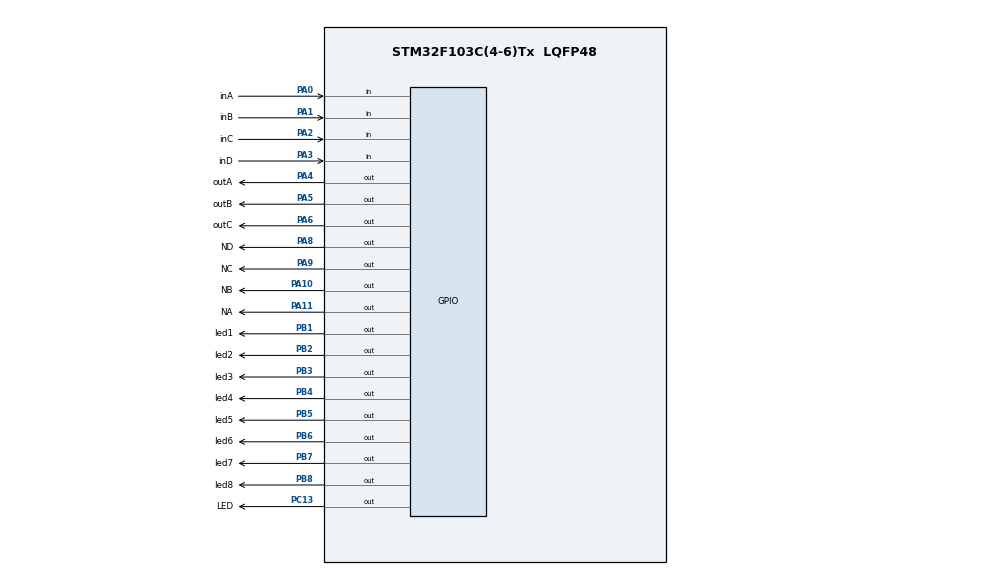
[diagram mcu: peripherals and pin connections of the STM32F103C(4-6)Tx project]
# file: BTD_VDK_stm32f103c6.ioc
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Mcu.Family=STM32F1
Mcu.Name=STM32F103C(4-6)Tx
Mcu.Package=LQFP48
NVIC.PriorityGroup=NVIC_PRIORITYGROUP_4
PA0-WKUP.GPIO_Label=inA
PA0-WKUP.GPIO_PuPd=GPIO_PULLUP
PA0-WKUP.Signal=GPIO_Input
PA1.GPIO_Label=inB
PA1.GPIO_PuPd=GPIO_PULLUP
PA1.Signal=GPIO_Input
PA10.GPIO_Label=NB
PA10.GPIO_Speed=GPIO_SPEED_FREQ_LOW
PA10.PinState=GPIO_PIN_RESET
PA10.Signal=GPIO_Output
PA11.GPIO_Label=NA
PA11.GPIO_Speed=GPIO_SPEED_FREQ_LOW
PA11.PinState=GPIO_PIN_RESET
PA11.Signal=GPIO_Output
PA13.Mode=Serial_Wire
PA13.Signal=SYS_JTMS-SWDIO
PA14.Mode=Serial_Wire
PA14.Signal=SYS_JTCK-SWCLK
PA2.GPIO_Label=inC
PA2.GPIO_PuPd=GPIO_PULLUP
PA2.Signal=GPIO_Input
PA3.GPIO_Label=inD
PA3.GPIO_PuPd=GPIO_PULLUP
PA3.Signal=GPIO_Input
PA4.GPIO_Label=outA
PA4.GPIO_Speed=GPIO_SPEED_FREQ_LOW
PA4.PinState=GPIO_PIN_RESET
PA4.Signal=GPIO_Output
PA5.GPIO_Label=outB
PA5.GPIO_Speed=GPIO_SPEED_FREQ_LOW
PA5.PinState=GPIO_PIN_RESET
PA5.Signal=GPIO_Output
PA6.GPIO_Label=outC
PA6.GPIO_Speed=GPIO_SPEED_FREQ_LOW
PA6.PinState=GPIO_PIN_RESET
PA6.Signal=GPIO_Output
PA8.GPIO_Label=ND
PA8.GPIO_Speed=GPIO_SPEED_FREQ_LOW
PA8.PinState=GPIO_PIN_RESET
PA8.Signal=GPIO_Output
PA9.GPIO_Label=NC
PA9.GPIO_Speed=GPIO_SPEED_FREQ_LOW
PA9.PinState=GPIO_PIN_RESET
PA9.Signal=GPIO_Output
PB1.GPIO_Label=led1
PB1.GPIO_Speed=GPIO_SPEED_FREQ_LOW
PB1.PinState=GPIO_PIN_RESET
PB1.Signal=GPIO_Output
PB2.GPIO_Label=led2
PB2.GPIO_Speed=GPIO_SPEED_FREQ_LOW
PB2.PinState=GPIO_PIN_RESET
PB2.Signal=GPIO_Output
PB3.GPIO_Label=led3
PB3.GPIO_Speed=GPIO_SPEED_FREQ_LOW
PB3.PinState=GPIO_PIN_RESET
PB3.Signal=GPIO_Output
PB4.GPIO_Label=led4
PB4.GPIO_Speed=GPIO_SPEED_FREQ_LOW
PB4.PinState=GPIO_PIN_RESET
PB4.Signal=GPIO_Output
PB5.GPIO_Label=led5
PB5.GPIO_Speed=GPIO_SPEED_FREQ_LOW
PB5.PinState=GPIO_PIN_RESET
PB5.Signal=GPIO_Output
PB6.GPIO_Label=led6
PB6.GPIO_Speed=GPIO_SPEED_FREQ_LOW
PB6.PinState=GPIO_PIN_RESET
PB6.Signal=GPIO_Output
PB7.GPIO_Label=led7
PB7.GPIO_Speed=GPIO_SPEED_FREQ_LOW
PB7.PinState=GPIO_PIN_RESET
PB7.Signal=GPIO_Output
PB8.GPIO_Label=led8
PB8.GPIO_Speed=GPIO_SPEED_FREQ_LOW
PB8.PinState=GPIO_PIN_RESET
PB8.Signal=GPIO_Output
PC13-TAMPER-RTC.GPIO_Label=LED
PC13-TAMPER-RTC.Signal=GPIO_Output
ProjectManager.HeapSize=0x200
ProjectManager.StackSize=0x400
ProjectManager.TargetToolchain=MDK-ARM V5.32
RCC.APB1Freq_Value=8000000
RCC.APB2Freq_Value=8000000
board=custom

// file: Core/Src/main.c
/* USER CODE BEGIN Header */
/**
  ******************************************************************************
  * @file           : main.c
  * @brief          : Main program body
  ******************************************************************************
  * @attention
  *
  * Copyright (c) 2022 STMicroelectronics.
  * All rights reserved.
  *
  * This software is licensed under terms that can be found in the LICENSE file
  * in the root directory of this software component.
  * If no LICENSE file comes with this software, it is provided AS-IS.
  *
  ******************************************************************************
  */
/* USER CODE END Header */
#include "main.h"

/* USER CODE BEGIN Includes */
#include "display.h"
#include "keypad.h"
#include "math.h"
/* USER CODE END Includes */

/* USER CODE BEGIN PM */
void PRESSKEY(unsigned char array[], uint8_t *t, uint8_t *enter);
/* USER CODE END PM */

/* USER CODE BEGIN PV */
uint8_t var = 0;								// bien kiem tra thu tu led
uint8_t tms = 0;								// bien kiem tra so lan nhap
uint8_t enter = 0;							//  enter
uint32_t pass = 12345678;			// mat khau dat san
uint32_t check = 0;							//bien check matkhau
uint8_t LATCH[8] = {10,10,10,10,10,10,10,10}; 		//  latch keypress
uint8_t ERR[8] = {11,11,11,11,11,11,11,11}; 			// trang thai hien loi

/* USER CODE END PV */

void SystemClock_Config(void);
static void MX_GPIO_Init(void);

int main(void)
{

  /* MCU Configuration--------------------------------------------------------*/

  /* Reset of all peripherals, Initializes the Flash interface and the Systick. */
  HAL_Init();

  /* Configure the system clock */
  SystemClock_Config();

  /* Initialize all configured peripherals */
  MX_GPIO_Init();
  /* USER CODE BEGIN 2 */
	HAL_GPIO_WritePin(GPIOC, GPIO_PIN_13, GPIO_PIN_SET);
  /* USER CODE END 2 */

  /* Infinite loop */
  while (1)
  {

    /* USER CODE BEGIN 3 */
		PRESSKEY(LATCH, &var, &enter);	 // quet phim
		if(var>8) var--;
		if(tms==3)												//kiem tra xem nhap qua 3 lan chua
		{
			while(tms==3)
				DISPLAY(ERR);									// hien thi da nhap qua 3 lan, khong cho nhap tiep
		}

		DISPLAY(LATCH);										// hien thi so da nhap

		if(enter)													// kiem tra da nhan enter chua?
		{
			for(int j=0; j<8;j++)						// kiem tra mat khau co dung khong?
							check = check + LATCH[j]*pow(10,(7-j));
			if(check == pass)								// neu mat khau dung
			{
					while(check == pass)
					{
							HAL_GPIO_WritePin(GPIOC, GPIO_PIN_13, GPIO_PIN_RESET); // MO KHOA
						for(int b=0; b<8; b++)			// hien thi 8 so 1 de the hien mat khau dung
								LATCH[b]=1;
						DISPLAY(LATCH);
					}
			}
			else									//neu mat khau sai
			{
				tms++;
				DISPLAY(ERR);				// hien thi nhap sai
				HAL_Delay(500);
				var = 0;						// gan cac gia tri ve initial
				check = 0;
				for(int k=0; k<8;k++)
					LATCH[k]=10;
			}
			enter=0;
		}
}
  /* USER CODE END 3 */
}

void SystemClock_Config(void)
{
  RCC_OscInitTypeDef RCC_OscInitStruct = {0};
  RCC_ClkInitTypeDef RCC_ClkInitStruct = {0};

  /** Initializes the RCC Oscillators according to the specified parameters
  * in the RCC_OscInitTypeDef structure.
  */
  RCC_OscInitStruct.OscillatorType = RCC_OSCILLATORTYPE_HSI;
  RCC_OscInitStruct.HSIState = RCC_HSI_ON;
  RCC_OscInitStruct.HSICalibrationValue = RCC_HSICALIBRATION_DEFAULT;
  RCC_OscInitStruct.PLL.PLLState = RCC_PLL_NONE;
  if (HAL_RCC_OscConfig(&RCC_OscInitStruct) != HAL_OK)
  {
    Error_Handler();
  }

  /** Initializes the CPU, AHB and APB buses clocks
  */
  RCC_ClkInitStruct.ClockType = RCC_CLOCKTYPE_HCLK|RCC_CLOCKTYPE_SYSCLK
                              |RCC_CLOCKTYPE_PCLK1|RCC_CLOCKTYPE_PCLK2;
  RCC_ClkInitStruct.SYSCLKSource = RCC_SYSCLKSOURCE_HSI;
  RCC_ClkInitStruct.AHBCLKDivider = RCC_SYSCLK_DIV1;
  RCC_ClkInitStruct.APB1CLKDivider = RCC_HCLK_DIV1;
  RCC_ClkInitStruct.APB2CLKDivider = RCC_HCLK_DIV1;

  if (HAL_RCC_ClockConfig(&RCC_ClkInitStruct, FLASH_LATENCY_0) != HAL_OK)
  {
    Error_Handler();
  }
}

static void MX_GPIO_Init(void)
{
  GPIO_InitTypeDef GPIO_InitStruct = {0};

  /* GPIO Ports Clock Enable */
  __HAL_RCC_GPIOC_CLK_ENABLE();
  __HAL_RCC_GPIOA_CLK_ENABLE();
  __HAL_RCC_GPIOB_CLK_ENABLE();

  /*Configure GPIO pin Output Level */
  HAL_GPIO_WritePin(LED_GPIO_Port, LED_Pin, GPIO_PIN_RESET);

  /*Configure GPIO pin Output Level */
  HAL_GPIO_WritePin(GPIOA, outA_Pin|outB_Pin|outC_Pin|ND_Pin
                          |NC_Pin|NB_Pin|NA_Pin, GPIO_PIN_RESET);

  /*Configure GPIO pin Output Level */
  HAL_GPIO_WritePin(GPIOB, l1_Pin|l2_Pin|l3_Pin|l4_Pin
                          |l5_Pin|l6_Pin|l7_Pin|l8_Pin, GPIO_PIN_RESET);

  /*Configure GPIO pin : LED_Pin */
  GPIO_InitStruct.Pin = LED_Pin;
  GPIO_InitStruct.Mode = GPIO_MODE_OUTPUT_PP;
  GPIO_InitStruct.Pull = GPIO_NOPULL;
  GPIO_InitStruct.Speed = GPIO_SPEED_FREQ_LOW;
  HAL_GPIO_Init(LED_GPIO_Port, &GPIO_InitStruct);

  /*Configure GPIO pins : inA_Pin inB_Pin inC_Pin inD_Pin */
  GPIO_InitStruct.Pin = inA_Pin|inB_Pin|inC_Pin|inD_Pin;
  GPIO_InitStruct.Mode = GPIO_MODE_INPUT;
  GPIO_InitStruct.Pull = GPIO_PULLUP;
  HAL_GPIO_Init(GPIOA, &GPIO_InitStruct);

  /*Configure GPIO pins : outA_Pin outB_Pin outC_Pin ND_Pin
                           NC_Pin NB_Pin NA_Pin */
  GPIO_InitStruct.Pin = outA_Pin|outB_Pin|outC_Pin|ND_Pin
                          |NC_Pin|NB_Pin|NA_Pin;
  GPIO_InitStruct.Mode = GPIO_MODE_OUTPUT_PP;
  GPIO_InitStruct.Pull = GPIO_NOPULL;
  GPIO_InitStruct.Speed = GPIO_SPEED_FREQ_LOW;
  HAL_GPIO_Init(GPIOA, &GPIO_InitStruct);

  /*Configure GPIO pins : l1_Pin l2_Pin l3_Pin l4_Pin
                           l5_Pin l6_Pin l7_Pin l8_Pin */
  GPIO_InitStruct.Pin = l1_Pin|l2_Pin|l3_Pin|l4_Pin
                          |l5_Pin|l6_Pin|l7_Pin|l8_Pin;
  GPIO_InitStruct.Mode = GPIO_MODE_OUTPUT_PP;
  GPIO_InitStruct.Pull = GPIO_NOPULL;
  GPIO_InitStruct.Speed = GPIO_SPEED_FREQ_LOW;
  HAL_GPIO_Init(GPIOB, &GPIO_InitStruct);

}

void Error_Handler(void)
{
  __disable_irq();
  while (1)
  {
  }
}
